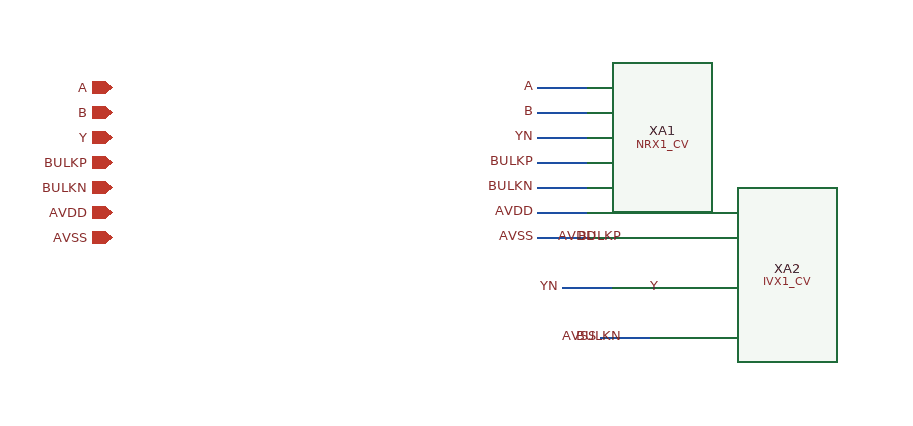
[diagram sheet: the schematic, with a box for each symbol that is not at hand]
v {xschem version=3.0.0 file_version=1.2 }
C {devices/iopin.sym} 0 0 0 0{name=p0 lab=A}
C {devices/iopin.sym} 0 20 0 0{name=p1 lab=B}
C {devices/iopin.sym} 0 40 0 0{name=p2 lab=Y}
C {devices/iopin.sym} 0 60 0 0{name=p3 lab=BULKP}
C {devices/iopin.sym} 0 80 0 0{name=p4 lab=BULKN}
C {devices/iopin.sym} 0 100 0 0{name=p5 lab=AVDD}
C {devices/iopin.sym} 0 120 0 0{name=p6 lab=AVSS}
C {SUN_SAR9B_SK130NM/NRX1_CV.sym} 400 0 0 0 {name=XA1}
N 340.0 0.0 380.0 0.0{lab=A}
C {devices/lab_pin.sym} 340.0 0.0 0 0  {name=l0 sig_type=std_logic lab=A }
N 340.0 20.0 380.0 20.0{lab=B}
C {devices/lab_pin.sym} 340.0 20.0 0 0  {name=l1 sig_type=std_logic lab=B }
N 340.0 40.0 380.0 40.0{lab=YN}
C {devices/lab_pin.sym} 340.0 40.0 0 0  {name=l2 sig_type=std_logic lab=YN }
N 340.0 60.0 380.0 60.0{lab=BULKP}
C {devices/lab_pin.sym} 340.0 60.0 0 0  {name=l3 sig_type=std_logic lab=BULKP }
N 340.0 80.0 380.0 80.0{lab=BULKN}
C {devices/lab_pin.sym} 340.0 80.0 0 0  {name=l4 sig_type=std_logic lab=BULKN }
N 340.0 100.0 380.0 100.0{lab=AVDD}
C {devices/lab_pin.sym} 340.0 100.0 0 0  {name=l5 sig_type=std_logic lab=AVDD }
N 340.0 120.0 380.0 120.0{lab=AVSS}
C {devices/lab_pin.sym} 340.0 120.0 0 0  {name=l6 sig_type=std_logic lab=AVSS }
C {SUN_SAR9B_SK130NM/IVX1_CV.sym} 400 160 0 0 {name=XA2}
N 360.0 160.0 400.0 160.0{lab=YN}
C {devices/lab_pin.sym} 360.0 160.0 0 0  {name=l7 sig_type=std_logic lab=YN }
N 440.0 160.0 480.0 160.0{lab=Y}
C {devices/lab_pin.sym} 440.0 160.0 0 0  {name=l8 sig_type=std_logic lab=Y }
N 410.0 120.0 450.0 120.0{lab=BULKP}
C {devices/lab_pin.sym} 410.0 120.0 0 0  {name=l9 sig_type=std_logic lab=BULKP }
N 410.0 200.0 450.0 200.0{lab=BULKN}
C {devices/lab_pin.sym} 410.0 200.0 0 0  {name=l10 sig_type=std_logic lab=BULKN }
N 390.0 120.0 430.0 120.0{lab=AVDD}
C {devices/lab_pin.sym} 390.0 120.0 0 0  {name=l11 sig_type=std_logic lab=AVDD }
N 390.0 200.0 430.0 200.0{lab=AVSS}
C {devices/lab_pin.sym} 390.0 200.0 0 0  {name=l12 sig_type=std_logic lab=AVSS }
